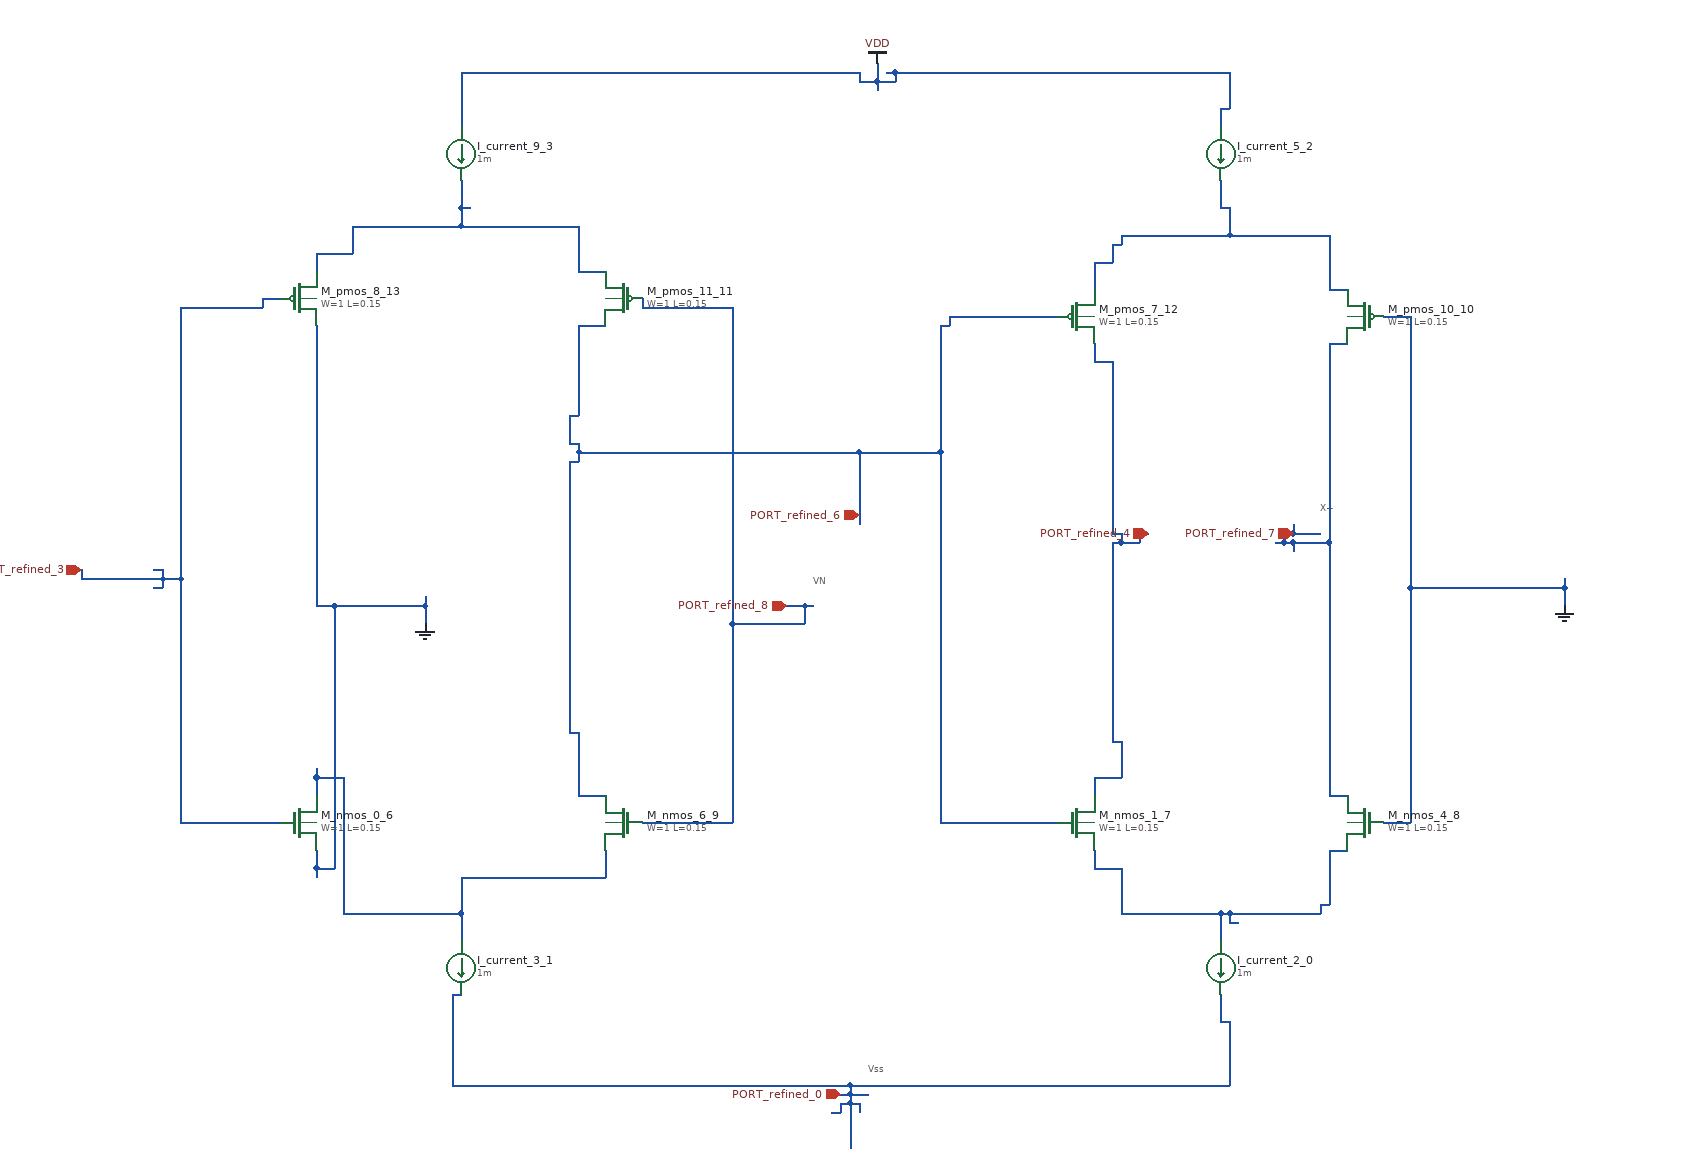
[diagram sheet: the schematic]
v {xschem version=3.4.8 file_version=1.2}
G {}
K {}
V {}
S {}
E {}
C {devices/isource.sym} 1360 1080 0 0 {name="I_current_2_0" value=1m}
C {devices/isource.sym} 520 1080 0 0 {name="I_current_3_1" value=1m}
C {devices/isource.sym} 1360 180 0 0 {name="I_current_5_2" value=1m}
C {devices/isource.sym} 520 180 0 0 {name="I_current_9_3" value=1m}
C {devices/gnd.sym} 480 700 0 0 {name="l_gnd_12_4" lab="GND"}
C {devices/gnd.sym} 1740 680 0 0 {name="l_gnd_13_5" lab="GND"}
C {sky130_fd_pr/nfet3_01v8.sym} 340 920 2 1 {name="M_nmos_0_6"
W=1
L=0.15
body=GND
nf=1
mult=1
ad="expr('int((@nf + 1)/2) * @W / @nf * 0.29')"
pd="expr('2*int((@nf + 1)/2) * (@W / @nf + 0.29)')"
as="expr('int((@nf + 2)/2) * @W / @nf * 0.29')"
ps="expr('2*int((@nf + 2)/2) * (@W / @nf + 0.29)')"
nrd="expr('0.29 / @W ')" nrs="expr('0.29 / @W ')"
sa=0 sb=0 sd=0
model=nfet_01v8
spiceprefix=X
}
C {sky130_fd_pr/nfet3_01v8.sym} 1200 920 0 0 {name="M_nmos_1_7"
W=1
L=0.15
body=GND
nf=1
mult=1
ad="expr('int((@nf + 1)/2) * @W / @nf * 0.29')"
pd="expr('2*int((@nf + 1)/2) * (@W / @nf + 0.29)')"
as="expr('int((@nf + 2)/2) * @W / @nf * 0.29')"
ps="expr('2*int((@nf + 2)/2) * (@W / @nf + 0.29)')"
nrd="expr('0.29 / @W ')" nrs="expr('0.29 / @W ')"
sa=0 sb=0 sd=0
model=nfet_01v8
spiceprefix=X
}
C {sky130_fd_pr/nfet3_01v8.sym} 1520 920 0 1 {name="M_nmos_4_8"
W=1
L=0.15
body=GND
nf=1
mult=1
ad="expr('int((@nf + 1)/2) * @W / @nf * 0.29')"
pd="expr('2*int((@nf + 1)/2) * (@W / @nf + 0.29)')"
as="expr('int((@nf + 2)/2) * @W / @nf * 0.29')"
ps="expr('2*int((@nf + 2)/2) * (@W / @nf + 0.29)')"
nrd="expr('0.29 / @W ')" nrs="expr('0.29 / @W ')"
sa=0 sb=0 sd=0
model=nfet_01v8
spiceprefix=X
}
C {sky130_fd_pr/nfet3_01v8.sym} 700 920 0 1 {name="M_nmos_6_9"
W=1
L=0.15
body=GND
nf=1
mult=1
ad="expr('int((@nf + 1)/2) * @W / @nf * 0.29')"
pd="expr('2*int((@nf + 1)/2) * (@W / @nf + 0.29)')"
as="expr('int((@nf + 2)/2) * @W / @nf * 0.29')"
ps="expr('2*int((@nf + 2)/2) * (@W / @nf + 0.29)')"
nrd="expr('0.29 / @W ')" nrs="expr('0.29 / @W ')"
sa=0 sb=0 sd=0
model=nfet_01v8
spiceprefix=X
}
C {sky130_fd_pr/pfet3_01v8.sym} 1520 360 0 1 {name="M_pmos_10_10"
W=1
L=0.15
body=VDD
nf=1
mult=1
ad="expr('int((@nf + 1)/2) * @W / @nf * 0.29')"
pd="expr('2*int((@nf + 1)/2) * (@W / @nf + 0.29)')"
as="expr('int((@nf + 2)/2) * @W / @nf * 0.29')"
ps="expr('2*int((@nf + 2)/2) * (@W / @nf + 0.29)')"
nrd="expr('0.29 / @W ')" nrs="expr('0.29 / @W ')"
sa=0 sb=0 sd=0
model=pfet_01v8
spiceprefix=X
}
C {sky130_fd_pr/pfet3_01v8.sym} 700 340 0 1 {name="M_pmos_11_11"
W=1
L=0.15
body=VDD
nf=1
mult=1
ad="expr('int((@nf + 1)/2) * @W / @nf * 0.29')"
pd="expr('2*int((@nf + 1)/2) * (@W / @nf + 0.29)')"
as="expr('int((@nf + 2)/2) * @W / @nf * 0.29')"
ps="expr('2*int((@nf + 2)/2) * (@W / @nf + 0.29)')"
nrd="expr('0.29 / @W ')" nrs="expr('0.29 / @W ')"
sa=0 sb=0 sd=0
model=pfet_01v8
spiceprefix=X
}
C {sky130_fd_pr/pfet3_01v8.sym} 1200 360 0 0 {name="M_pmos_7_12"
W=1
L=0.15
body=VDD
nf=1
mult=1
ad="expr('int((@nf + 1)/2) * @W / @nf * 0.29')"
pd="expr('2*int((@nf + 1)/2) * (@W / @nf + 0.29)')"
as="expr('int((@nf + 2)/2) * @W / @nf * 0.29')"
ps="expr('2*int((@nf + 2)/2) * (@W / @nf + 0.29)')"
nrd="expr('0.29 / @W ')" nrs="expr('0.29 / @W ')"
sa=0 sb=0 sd=0
model=pfet_01v8
spiceprefix=X
}
C {sky130_fd_pr/pfet3_01v8.sym} 340 340 0 0 {name="M_pmos_8_13"
W=1
L=0.15
body=VDD
nf=1
mult=1
ad="expr('int((@nf + 1)/2) * @W / @nf * 0.29')"
pd="expr('2*int((@nf + 1)/2) * (@W / @nf + 0.29)')"
as="expr('int((@nf + 2)/2) * @W / @nf * 0.29')"
ps="expr('2*int((@nf + 2)/2) * (@W / @nf + 0.29)')"
nrd="expr('0.29 / @W ')" nrs="expr('0.29 / @W ')"
sa=0 sb=0 sd=0
model=pfet_01v8
spiceprefix=X
}
C {devices/ipin.sym} 960 580 0 0 {name="p_port_14_14" lab="PORT_refined_6"}
C {devices/ipin.sym} 100 640 0 0 {name="p_port_15_15" lab="PORT_refined_3"}
C {devices/ipin.sym} 1280 600 0 0 {name="p_port_16_16" lab="PORT_refined_4"}
C {devices/ipin.sym} 880 680 0 0 {name="p_port_18_17" lab="PORT_refined_8"}
T {VN} 910 640 0 0 0.25 0.25 {}
C {devices/ipin.sym} 1440 600 0 0 {name="p_port_19_18" lab="PORT_refined_7"}
T {X+} 1470 560 0 0 0.25 0.25 {}
C {devices/ipin.sym} 940 1220 0 0 {name="p_port_20_19" lab="PORT_refined_0"}
T {Vss} 970 1180 0 0 0.25 0.25 {}
C {devices/vdd.sym} 980 80 0 0 {name="l_vdd_17_20" lab="VDD"}
N 930 1240 940 1240 {}
N 940 1230 950 1230 {}
N 950 1230 960 1230 {}
N 940 1220 950 1220 {}
N 950 1220 970 1220 {}
N 510 1210 950 1210 {}
N 950 1210 1370 1210 {}
N 1360 1140 1370 1140 {}
N 510 1110 520 1110 {}
N 510 1210 510 1110 {}
N 940 1240 940 1230 {}
N 950 1280 950 1230 {}
N 950 1230 950 1220 {}
N 950 1220 950 1210 {}
N 960 1240 960 1230 {}
N 1360 1140 1360 1110 {}
N 1370 1210 1370 1140 {}
N 360 970 380 970 {}
N 1540 920 1570 920 {}
N 360 680 380 680 {}
N 380 680 480 680 {}
N 1570 660 1740 660 {}
N 1540 360 1570 360 {}
N 360 980 360 970 {}
N 360 970 360 950 {}
N 360 680 360 370 {}
N 380 970 380 680 {}
N 480 700 480 680 {}
N 480 680 480 670 {}
N 1570 920 1570 660 {}
N 1570 660 1570 360 {}
N 1740 680 1740 660 {}
N 1740 660 1740 650 {}
N 650 310 680 310 {}
N 360 290 400 290 {}
N 400 260 520 260 {}
N 520 260 650 260 {}
N 520 240 530 240 {}
N 360 310 360 290 {}
N 400 290 400 260 {}
N 520 260 520 240 {}
N 520 240 520 210 {}
N 650 310 650 260 {}
N 1360 130 1370 130 {}
N 960 100 980 100 {}
N 980 100 1000 100 {}
N 520 90 960 90 {}
N 990 90 1000 90 {}
N 1000 90 1370 90 {}
N 520 150 520 90 {}
N 960 100 960 90 {}
N 980 110 980 100 {}
N 980 100 980 80 {}
N 1000 100 1000 90 {}
N 1360 150 1360 130 {}
N 1370 130 1370 90 {}
N 390 1020 520 1020 {}
N 520 980 680 980 {}
N 360 870 390 870 {}
N 360 890 360 870 {}
N 360 870 360 860 {}
N 390 1020 390 870 {}
N 520 1050 520 1020 {}
N 520 1020 520 980 {}
N 680 980 680 950 {}
N 210 920 320 920 {}
N 180 660 190 660 {}
N 100 650 190 650 {}
N 190 650 210 650 {}
N 180 640 190 640 {}
N 210 350 300 350 {}
N 300 340 320 340 {}
N 100 650 100 640 {}
N 190 660 190 650 {}
N 190 650 190 640 {}
N 210 920 210 650 {}
N 210 650 210 350 {}
N 300 350 300 340 {}
N 1220 870 1250 870 {}
N 1240 830 1250 830 {}
N 1240 610 1250 610 {}
N 1250 610 1270 610 {}
N 1240 600 1250 600 {}
N 1270 600 1280 600 {}
N 1220 410 1240 410 {}
N 1220 890 1220 870 {}
N 1220 410 1220 390 {}
N 1240 830 1240 610 {}
N 1240 600 1240 410 {}
N 1250 870 1250 830 {}
N 1250 610 1250 600 {}
N 1270 610 1270 600 {}
N 1370 1030 1380 1030 {}
N 1250 1020 1360 1020 {}
N 1360 1020 1370 1020 {}
N 1370 1020 1470 1020 {}
N 1470 1010 1480 1010 {}
N 1220 970 1250 970 {}
N 1480 950 1500 950 {}
N 1220 970 1220 950 {}
N 1250 1020 1250 970 {}
N 1360 1050 1360 1020 {}
N 1370 1030 1370 1020 {}
N 1470 1020 1470 1010 {}
N 1480 1010 1480 950 {}
N 1050 920 1180 920 {}
N 650 890 680 890 {}
N 640 820 650 820 {}
N 640 520 650 520 {}
N 650 510 960 510 {}
N 960 510 1050 510 {}
N 640 500 650 500 {}
N 640 470 650 470 {}
N 650 370 680 370 {}
N 1050 370 1060 370 {}
N 1060 360 1180 360 {}
N 640 820 640 520 {}
N 640 500 640 470 {}
N 650 890 650 820 {}
N 650 520 650 510 {}
N 650 510 650 500 {}
N 650 470 650 370 {}
N 960 590 960 580 {}
N 960 580 960 510 {}
N 1050 920 1050 510 {}
N 1050 510 1050 370 {}
N 1060 370 1060 360 {}
N 1480 890 1500 890 {}
N 1420 610 1430 610 {}
N 1430 610 1440 610 {}
N 1440 610 1480 610 {}
N 1430 600 1440 600 {}
N 1440 600 1470 600 {}
N 1480 390 1500 390 {}
N 1430 610 1430 600 {}
N 1440 620 1440 610 {}
N 1440 600 1440 590 {}
N 1480 890 1480 610 {}
N 1480 610 1480 390 {}
N 720 920 820 920 {}
N 820 700 900 700 {}
N 880 680 900 680 {}
N 900 680 910 680 {}
N 720 350 820 350 {}
N 720 350 720 340 {}
N 820 920 820 700 {}
N 820 700 820 350 {}
N 900 700 900 680 {}
N 1480 330 1500 330 {}
N 1220 300 1240 300 {}
N 1240 280 1250 280 {}
N 1250 270 1370 270 {}
N 1370 270 1480 270 {}
N 1360 240 1370 240 {}
N 1220 330 1220 300 {}
N 1240 300 1240 280 {}
N 1250 280 1250 270 {}
N 1360 240 1360 210 {}
N 1370 270 1370 240 {}
N 1480 330 1480 270 {}
